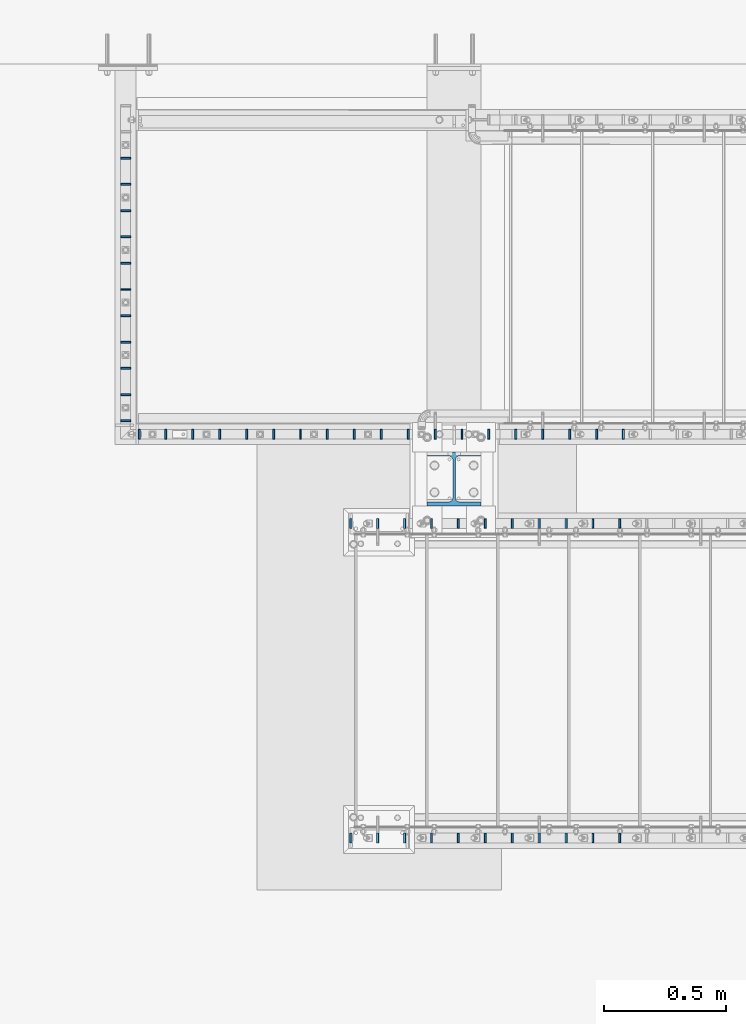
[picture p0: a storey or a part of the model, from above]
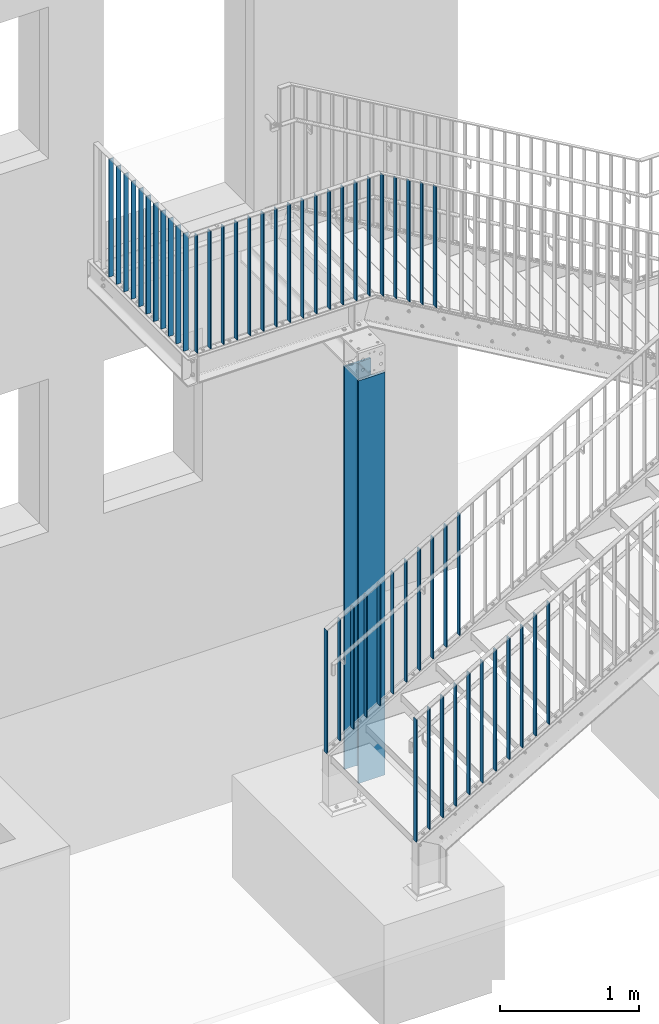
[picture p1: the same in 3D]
Properties of the parts of a building model (IFC2X3)

# File
Description: ViewDefinition[CoordinationView_V2.0]
File name: Modell Treppe Ost Unterschlei?heim_ifc2x3.ifc
Time: 2026-07-28T09:38:39
Organization: Stadt Unterschlei?heim
Written by: IFC Toolkit 2.0.26.0
Made in: Advance Steel 2024

# IfcBuildingStorey, Default Storey
In: Struktur 1
Elevation: 0 mm

# IfcBeam: - (85)
In: Default Storey
Pset_BeamCommon - Reference: nicht definiert; Slope: 0 deg; IsExternal: no; LoadBearing: no
Name | Description = Section | Material | Span (mm) | SectionFamily
- | U240 | S235JR | 1470 | Channels DIN18800-1
- | U240 | S235JR | 344.999 | Channels DIN18800-1
- | L40X4 | S235JR | 530.703 | Angle_eq DIN18800-1
- | L40X4 | S235JR | 1665.7 | Angle_eq DIN18800-1
- | FL40X8 | S235JR | 208.357 | Flat nach DIN
- | FL40X8 | S235JR | 257.791 | Flat nach DIN
- | RHS?30x2 | 1.4301 | 129.796 | RHS rund EN10210-2 1990
- | RHS?30x2 | 1.4301 | 590.298 | RHS rund EN10210-2 1990
- | U240 | S235JR | 1530 | Channels DIN18800-1
2 x - | FL40X8 | S235JR | 1367.5 | Flat nach DIN
- | U240 | S235JR | 3020 | Channels DIN18800-1
2 x - | FL40X8 | S235JR | 2975 | Flat nach DIN
- | RHS?30x2 | 1.4301 | 111.001 | RHS rund EN10210-2 1990
- | RHS?30x2 | 1.4301 | 28.5 | RHS rund EN10210-2 1990
- | FL50X6 | S235JR | 1348 | Flat nach DIN
- | RHS?30x2 | 1.4301 | 2698 | RHS rund EN10210-2 1990
2 x - | RD20 | S235JR | 1218.6 | Round nach DIN
2 x - | RD20 | S235JR | 1063.78 | Round nach DIN
- | HEB220 | S235JR | 3000 | HEB DIN18800-1
- | HEB220 | S235JR | 1755 | HEB DIN18800-1
20 x - | Antrittskante Giro 70 mm | S235JR | 1194 | Usr Antrittskante erh?ht
- | FL40X8 | S235JR | 48.5661 | Flat nach DIN
2 x - | Antrittskante Giro 70 mm | S235JR | 1198 | Usr Antrittskante erh?ht
- | L40X4 | S235JR | 1511.3 | Angle_eq DIN18800-1
- | L40X4 | S235JR | 173.296 | Angle_eq DIN18800-1
- | FL40X8 | S235JR | 97.9995 | Flat nach DIN
2 x - | U240 | S235JR | 1474.71 | Channels DIN18800-1
- | RHS?30x2 | 1.4301 | 245.79 | RHS rund EN10210-2 1990
- | RHS?30x2 | 1.4301 | 335.499 | RHS rund EN10210-2 1990
- | T120 | S235JR | 1115 | T DIN18800-1
2 x - | U240 | S235JR | 214.999 | Channels DIN18800-1
2 x - | FL40X8 | S235JR | 192.499 | Flat nach DIN
2 x - | FL40X8 | S235JR | 201.499 | Flat nach DIN
2 x - | RHS?30x2 | 1.4301 | 234 | RHS rund EN10210-2 1990
2 x - | FL40X8 | S235JR | 1358 | Flat nach DIN
2 x - | FL40X8 | S235JR | 418.797 | Flat nach DIN
2 x - | FL40X8 | S235JR | 1308.57 | Flat nach DIN
- | RHS?30x2 | 1.4301 | 1359 | RHS rund EN10210-2 1990
- | RHS?30x2 | 1.4301 | 281.299 | RHS rund EN10210-2 1990
- | FL40X8 | S235JR | 1071.59 | Flat nach DIN
2 x - | FL40X8 | S235JR | 404.202 | Flat nach DIN
- | FL40X8 | S235JR | 1022.16 | Flat nach DIN
- | RHS?30x2 | 1.4301 | 266.703 | RHS rund EN10210-2 1990
- | RHS?30x2 | 1.4301 | 1029.09 | RHS rund EN10210-2 1990
2 x - | FL40X8 | S235JR | 238.796 | Flat nach DIN
- | U240 | S235JR | 1654.71 | Channels DIN18800-1
- | U240 | S235JR | 529.707 | Channels DIN18800-1
- | FL40X8 | S235JR | 509.364 | Flat nach DIN
- | FL40X8 | S235JR | 558.797 | Flat nach DIN
- | L40X4 | S235JR | 566.299 | Angle_eq DIN18800-1
- | L40X4 | S235JR | 1701.3 | Angle_eq DIN18800-1

# IfcBuildingElementProxy: - (73)
In: Default Storey
Name | Material
13 x  | 1.4301
4 x  | S235JR
56 x  | A2

# IfcColumn: - (246)
In: Default Storey
Pset_ColumnCommon - Reference: nicht definiert; Slope: 0 deg; IsExternal: no; LoadBearing: no
Name | Description = Section | Material | SectionFamily
205 x - | FL40X8 | S235JR | Flat nach DIN
2 x - | RHS?30x2 | 1.4301 | RHS rund EN10210-2 1990
35 x - | RD8 | 1.4301 | Round nach DIN
2 x - | HEB220 | S235JR | HEB DIN18800-1
2 x - | U240 | S235JR | Channels DIN18800-1

# IfcMechanicalFastener: - (216)
In: Default Storey
Name | NominalDiameter (mm) | NominalLength (mm)
101 x  | 12 | 45
13 x  | 16 | 45
2 x  | 16 | 170
80 x  | 12 | 35
4 x  | 20 | 70
4 x  | 12 | 40
4 x  | 6 | 20
6 x  | 16 | 55
2 x  | 12 | 130

# IfcMember: - (16)
In: Default Storey
Pset_MemberCommon - Reference: nicht definiert; Slope: 0 deg; IsExternal: no; LoadBearing: no
Name | Description = Section | Material | Span (mm) | SectionFamily
2 x - | RHS?30x2 | 1.4301 | 3362.76 | RHS rund EN10210-2 1990
2 x - | RHS?30x2 | 1.4301 | 3713.27 | RHS rund EN10210-2 1990
4 x - | FL40X8 | S235JR | 3356.83 | Flat nach DIN
2 x - | U240 | S235JR | 3419.38 | Channels DIN18800-1
2 x - | FL40X8 | S235JR | 3775.11 | Flat nach DIN
2 x - | U240 | S235JR | 3772.95 | Channels DIN18800-1
2 x - | FL40X8 | S235JR | 3713.27 | Flat nach DIN

# IfcPlate: - (129)
In: Default Storey
Description: -
Pset_PlateCommon - Reference: nicht definiert; IsExternal: no; LoadBearing: no
Name | Material
35 x - | S235JR 8 mm
14 x - | S235JR 20 mm
29 x - | S235JR 10 mm
4 x - | S235JR 5 mm
- | Thermostop 10 mm
- | Thermostop 6 mm
2 x - | S235JR 15 mm
2 x - | S235JR 30 mm
40 x - | S235JR 3 mm
- | S235JR 25 mm

# IfcPlate: Grating (25)
In: Default Storey
Description: -; Material: S235JR 40 mm
Pset_PlateCommon - Reference: nicht definiert; IsExternal: no; LoadBearing: no

# IfcPlate: Stiffener#0 (3)
In: Default Storey
Description: -; Material: S235JR 15 mm
Pset_PlateCommon - Reference: nicht definiert; IsExternal: no; LoadBearing: no

# IfcPlate: Stiffener#1 (13)
In: Default Storey
Description: -
Pset_PlateCommon - Reference: nicht definiert; IsExternal: no; LoadBearing: no
Name | Material
3 x Stiffener#1 | S235JR 15 mm
10 x Stiffener#1 | S235JR 10 mm

# IfcSlab: - (6)
In: Default Storey
Description: -
Pset_SlabCommon - Reference: nicht definiert; IsExternal: no; LoadBearing: no; Combustible: no; Compartmentation: no; PitchAngle: 0 deg
Name | Material
3 x - | C25/30 240 mm
- | C25/30 50 mm
2 x - | C25/30 900 mm

# IfcSlab: Gokoba_Estrich (3)
In: Default Storey
Description: -; Material: C25/30 60 mm
Pset_SlabCommon - Reference: nicht definiert; IsExternal: no; LoadBearing: no; Combustible: no; Compartmentation: no; PitchAngle: 0 deg

# IfcWall: -
In: Default Storey
Description: -; Material: C25/30 1775 mm
Pset_WallCommon - Reference: nicht definiert; Combustible: no; IsExternal: no; ExtendToStructure: no; LoadBearing: no; Compartmentation: no

# IfcWall: Gokoba_D?mmung
In: Default Storey
Description: -; Material: C25/30 1125 mm
Pset_WallCommon - Reference: nicht definiert; Combustible: no; IsExternal: no; ExtendToStructure: no; LoadBearing: no; Compartmentation: no

# IfcWall: Gokoba_Mauerwerk
In: Default Storey
Description: -; Material: C25/30 1000 mm
Pset_WallCommon - Reference: nicht definiert; Combustible: no; IsExternal: no; ExtendToStructure: no; LoadBearing: no; Compartmentation: no
